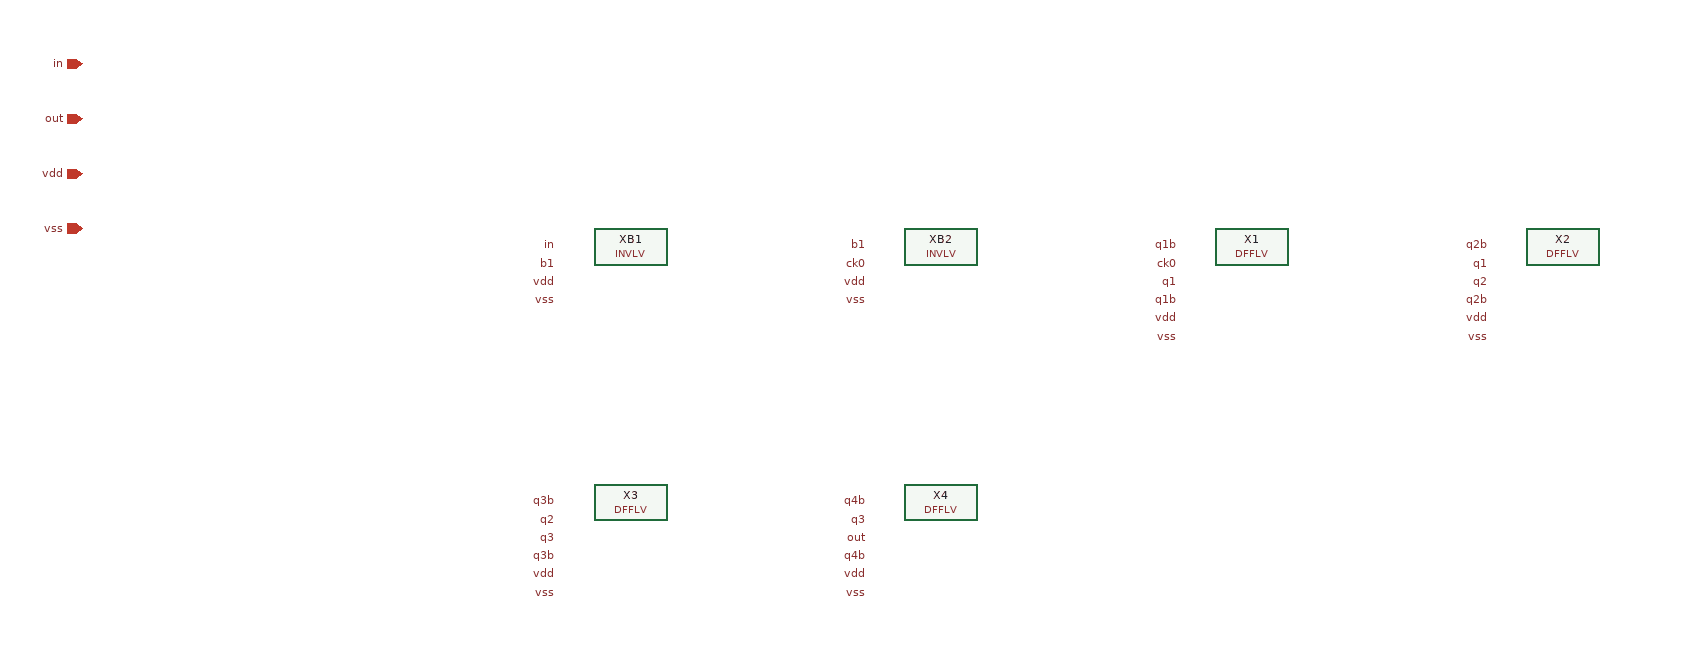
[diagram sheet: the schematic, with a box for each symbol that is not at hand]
v {xschem version=3.4.4 file_version=1.2}
G {}
K {}
V {}
S {}
E {}
C {devices/iopin.sym} -400 0 0 0 {name=p0 lab=in}
C {devices/iopin.sym} -400 60 0 0 {name=p1 lab=out}
C {devices/iopin.sym} -400 120 0 0 {name=p2 lab=vdd}
C {devices/iopin.sym} -400 180 0 0 {name=p3 lab=vss}
C {cplz_ls01/INVLV.sym} 200 200 0 0 {name=XB1}
C {devices/lab_pin.sym} 120 200 0 0 {name=l1 sig_type=std_logic lab=in}
C {devices/lab_pin.sym} 120 220 0 0 {name=l2 sig_type=std_logic lab=b1}
C {devices/lab_pin.sym} 120 240 0 0 {name=l3 sig_type=std_logic lab=vdd}
C {devices/lab_pin.sym} 120 260 0 0 {name=l4 sig_type=std_logic lab=vss}
C {cplz_ls01/INVLV.sym} 540 200 0 0 {name=XB2}
C {devices/lab_pin.sym} 460 200 0 0 {name=l5 sig_type=std_logic lab=b1}
C {devices/lab_pin.sym} 460 220 0 0 {name=l6 sig_type=std_logic lab=ck0}
C {devices/lab_pin.sym} 460 240 0 0 {name=l7 sig_type=std_logic lab=vdd}
C {devices/lab_pin.sym} 460 260 0 0 {name=l8 sig_type=std_logic lab=vss}
C {cplz_ls01/DFFLV.sym} 880 200 0 0 {name=X1}
C {devices/lab_pin.sym} 800 200 0 0 {name=l9 sig_type=std_logic lab=q1b}
C {devices/lab_pin.sym} 800 220 0 0 {name=l10 sig_type=std_logic lab=ck0}
C {devices/lab_pin.sym} 800 240 0 0 {name=l11 sig_type=std_logic lab=q1}
C {devices/lab_pin.sym} 800 260 0 0 {name=l12 sig_type=std_logic lab=q1b}
C {devices/lab_pin.sym} 800 280 0 0 {name=l13 sig_type=std_logic lab=vdd}
C {devices/lab_pin.sym} 800 300 0 0 {name=l14 sig_type=std_logic lab=vss}
C {cplz_ls01/DFFLV.sym} 1220 200 0 0 {name=X2}
C {devices/lab_pin.sym} 1140 200 0 0 {name=l15 sig_type=std_logic lab=q2b}
C {devices/lab_pin.sym} 1140 220 0 0 {name=l16 sig_type=std_logic lab=q1}
C {devices/lab_pin.sym} 1140 240 0 0 {name=l17 sig_type=std_logic lab=q2}
C {devices/lab_pin.sym} 1140 260 0 0 {name=l18 sig_type=std_logic lab=q2b}
C {devices/lab_pin.sym} 1140 280 0 0 {name=l19 sig_type=std_logic lab=vdd}
C {devices/lab_pin.sym} 1140 300 0 0 {name=l20 sig_type=std_logic lab=vss}
C {cplz_ls01/DFFLV.sym} 200 480 0 0 {name=X3}
C {devices/lab_pin.sym} 120 480 0 0 {name=l21 sig_type=std_logic lab=q3b}
C {devices/lab_pin.sym} 120 500 0 0 {name=l22 sig_type=std_logic lab=q2}
C {devices/lab_pin.sym} 120 520 0 0 {name=l23 sig_type=std_logic lab=q3}
C {devices/lab_pin.sym} 120 540 0 0 {name=l24 sig_type=std_logic lab=q3b}
C {devices/lab_pin.sym} 120 560 0 0 {name=l25 sig_type=std_logic lab=vdd}
C {devices/lab_pin.sym} 120 580 0 0 {name=l26 sig_type=std_logic lab=vss}
C {cplz_ls01/DFFLV.sym} 540 480 0 0 {name=X4}
C {devices/lab_pin.sym} 460 480 0 0 {name=l27 sig_type=std_logic lab=q4b}
C {devices/lab_pin.sym} 460 500 0 0 {name=l28 sig_type=std_logic lab=q3}
C {devices/lab_pin.sym} 460 520 0 0 {name=l29 sig_type=std_logic lab=out}
C {devices/lab_pin.sym} 460 540 0 0 {name=l30 sig_type=std_logic lab=q4b}
C {devices/lab_pin.sym} 460 560 0 0 {name=l31 sig_type=std_logic lab=vdd}
C {devices/lab_pin.sym} 460 580 0 0 {name=l32 sig_type=std_logic lab=vss}
